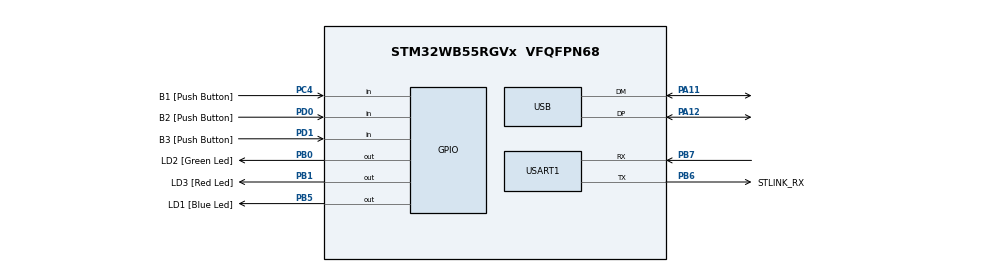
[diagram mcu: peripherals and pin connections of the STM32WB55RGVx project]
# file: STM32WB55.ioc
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Dma.Request0=USART1_TX
Dma.USART1_TX.0.Direction=DMA_MEMORY_TO_PERIPH
Dma.USART1_TX.0.EventEnable=DISABLE
Dma.USART1_TX.0.Instance=DMA1_Channel1
Dma.USART1_TX.0.MemDataAlignment=DMA_MDATAALIGN_BYTE
Dma.USART1_TX.0.MemInc=DMA_MINC_ENABLE
Dma.USART1_TX.0.Mode=DMA_NORMAL
Dma.USART1_TX.0.PeriphDataAlignment=DMA_PDATAALIGN_BYTE
Dma.USART1_TX.0.PeriphInc=DMA_PINC_DISABLE
Dma.USART1_TX.0.Polarity=HAL_DMAMUX_REQ_GEN_RISING
Dma.USART1_TX.0.Priority=DMA_PRIORITY_LOW
Dma.USART1_TX.0.RequestNumber=1
Dma.USART1_TX.0.SignalID=NONE
Dma.USART1_TX.0.SyncEnable=DISABLE
Dma.USART1_TX.0.SyncPolarity=HAL_DMAMUX_SYNC_NO_EVENT
Dma.USART1_TX.0.SyncRequestNumber=1
Dma.USART1_TX.0.SyncSignalID=NONE
Mcu.Family=STM32WB
Mcu.Name=STM32WB55RGVx
Mcu.Package=VFQFPN68
NVIC.DMA1_Channel1_IRQn=true\:0\:0\:false\:false\:true\:false\:true
NVIC.PriorityGroup=NVIC_PRIORITYGROUP_4
NVIC.TIM1_TRG_COM_TIM17_IRQn=true\:0\:0\:false\:false\:true\:false\:true
NVIC.TIM1_UP_TIM16_IRQn=true\:0\:0\:false\:false\:true\:true\:true
NVIC.TIM2_IRQn=true\:0\:0\:false\:false\:true\:true\:true
NVIC.TimeBase=TIM1_TRG_COM_TIM17_IRQn
NVIC.TimeBaseIP=TIM17
NVIC.USART1_IRQn=true\:0\:0\:false\:false\:true\:true\:true
OSC_IN.Mode=HSE-External-Oscillator
OSC_IN.Signal=RCC_OSC_IN
OSC_OUT.Mode=HSE-External-Oscillator
OSC_OUT.Signal=RCC_OSC_OUT
PA11.Mode=Device
PA11.Signal=USB_DM
PA12.Mode=Device
PA12.Signal=USB_DP
PA13.GPIO_Label=JTMS
PA13.Mode=Trace_Asynchronous_SW
PA13.Signal=SYS_JTMS-SWDIO
PA14.GPIO_Label=JTCK
PA14.Mode=Trace_Asynchronous_SW
PA14.Signal=SYS_JTCK-SWCLK
PB0.GPIO_Label=LD2 [Green Led]
PB0.GPIO_Speed=GPIO_SPEED_FREQ_VERY_HIGH
PB0.PinState=GPIO_PIN_RESET
PB0.Signal=GPIO_Output
PB1.GPIO_Label=LD3 [Red Led]
PB1.Signal=GPIO_Output
PB3.GPIO_Label=JTDO
PB3.Mode=Trace_Asynchronous_SW
PB3.Signal=SYS_JTDO-SWO
PB5.GPIO_Label=LD1 [Blue Led]
PB5.Signal=GPIO_Output
PB6.GPIO_Label=STLINK_RX
PB6.GPIO_PuPd=GPIO_PULLUP
PB6.Mode=Asynchronous
PB6.Signal=USART1_TX
PB7.Mode=Asynchronous
PB7.Signal=USART1_RX
PC13.Mode=SYS_WakeUp1
PC13.Signal=SYS_WKUP2
PC14-OSC32_IN.Mode=LSE-External-Oscillator
PC14-OSC32_IN.Signal=RCC_OSC32_IN
PC15-OSC32_OUT.Mode=LSE-External-Oscillator
PC15-OSC32_OUT.Signal=RCC_OSC32_OUT
PC4.GPIO_Label=B1 [Push Button]
PC4.Signal=GPIO_Input
PD0.GPIO_Label=B2 [Push Button]
PD0.Signal=GPIO_Input
PD1.GPIO_Label=B3 [Push Button]
PD1.Signal=GPIO_Input
ProjectManager.HeapSize=0x200
ProjectManager.StackSize=0x400
ProjectManager.TargetToolchain=STM32CubeIDE
RCC.ADCFreq_Value=96000000
RCC.AHB2CLKDivider=RCC_SYSCLK_DIV2
RCC.AHBFreq_Value=64000000
RCC.APB1Freq_Value=64000000
RCC.APB1TimFreq_Value=64000000
RCC.APB2Freq_Value=64000000
RCC.APB2TimFreq_Value=64000000
RCC.APB3Freq_Value=16000000
RCC.CortexFreq_Value=64000000
RCC.HCLKFreq_Value=64000000
RCC.HSEPRES=2
RCC.HSE_VALUE=32000000
RCC.HSI48_VALUE=48000000
RCC.HSI_VALUE=16000000
RCC.PLLM=RCC_PLLM_DIV2
RCC.PLLN=32
RCC.PLLR=RCC_PLLR_DIV4
RCC.PLLSAI1N=24
RCC.PLLSAI1Q=RCC_PLLQ_DIV4
RCC.PLLSourceVirtual=RCC_PLLSOURCE_HSE
RCC.SMPSCLockSelectionVirtual=RCC_SMPSCLKSOURCE_HSI
RCC.SMPSCLockSelectionVirtualVirtual=RCC_SMPSCLKSOURCE_HSI
RCC.SMPSDivider=1
RCC.SYSCLKFreq_VALUE=64000000
RCC.SYSCLKSource=RCC_SYSCLKSOURCE_PLLCLK
RCC.USBFreq_Value=48000000
RCC.VCOOutputFreq_Value=256000000
TIM2.AutoReloadPreload=TIM_AUTORELOAD_PRELOAD_ENABLE
TIM2.Channel-Output\ Compare1\ No\ Output=TIM_CHANNEL_1
TIM2.Channel-Output\ Compare2\ No\ Output=TIM_CHANNEL_2
TIM2.OC1Preload=DISABLE
TIM2.OC2Preload=DISABLE
TIM2.OCMode_1=TIM_OCMODE_TIMING
TIM2.OCMode_2=TIM_OCMODE_TIMING
TIM2.Period=0x0000FFFF
TIM2.Prescaler=64
TIM2.Pulse-Output\ Compare1\ No\ Output=2000
TIM2.Pulse-Output\ Compare2\ No\ Output=10000
USART1.VirtualMode-Asynchronous=VM_ASYNC
VP_CRC_VS_CRC.Mode=CRC_Activate
VP_RTC_VS_RTC_Activate.Mode=RTC_Enabled
VP_SYS_VS_tim17.Mode=TIM17
VP_TIM16_VS_ClockSourceINT.Mode=Enable_Timer
VP_TIM2_VS_ClockSourceINT.Mode=Internal
VP_TIM2_VS_no_output1.Mode=Output Compare1 No Output
VP_TIM2_VS_no_output2.Mode=Output Compare2 No Output
board=P-NUCLEO-WB55-Nucleo

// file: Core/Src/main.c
/* USER CODE BEGIN Header */
/**
  ******************************************************************************
  * @file           : main.c
  * @brief          : Main program body
  ******************************************************************************
  * @attention
  *
  * <h2><center>&copy; Copyright (c) 2022 STMicroelectronics.
  * All rights reserved.</center></h2>
  *
  * This software component is licensed by ST under BSD 3-Clause license,
  * the "License"; You may not use this file except in compliance with the
  * License. You may obtain a copy of the License at:
  *                        opensource.org/licenses/BSD-3-Clause
  *
  ******************************************************************************
  */
/* USER CODE END Header */

#include "main.h"

CRC_HandleTypeDef hcrc;

RTC_HandleTypeDef hrtc;

TIM_HandleTypeDef htim2;
TIM_HandleTypeDef htim16;

DMA_HandleTypeDef hdma_usart1_tx;

PCD_HandleTypeDef hpcd_USB_FS;

void SystemClock_Config(void);
static void MX_GPIO_Init(void);
static void MX_DMA_Init(void);
static void MX_USB_PCD_Init(void);
static void MX_CRC_Init(void);
static void MX_RTC_Init(void);
static void MX_TIM2_Init(void);
static void MX_USART1_UART_Init(void);
static void MX_TIM16_Init(void);

int main(void)
{

  /* MCU Configuration--------------------------------------------------------*/

  /* Reset of all peripherals, Initializes the Flash interface and the Systick. */
  HAL_Init();

  /* Configure the system clock */
  SystemClock_Config();

  /* Initialize all configured peripherals */
  MX_GPIO_Init();
  MX_DMA_Init();
  MX_USB_PCD_Init();
  MX_CRC_Init();
  MX_RTC_Init();
  MX_TIM2_Init();
  MX_USART1_UART_Init();
  MX_TIM16_Init();
  /* USER CODE BEGIN 2 */
  app_main_init();
  /* USER CODE END 2 */

  /* Infinite loop */
  /* USER CODE BEGIN WHILE */
  while (1)
  {
    app_main_idle();
    /* USER CODE END WHILE */

  }
}

void SystemClock_Config(void)
{
  RCC_OscInitTypeDef RCC_OscInitStruct = {0};
  RCC_ClkInitTypeDef RCC_ClkInitStruct = {0};
  RCC_PeriphCLKInitTypeDef PeriphClkInitStruct = {0};

  /** Configure the main internal regulator output voltage
  */
  __HAL_PWR_VOLTAGESCALING_CONFIG(PWR_REGULATOR_VOLTAGE_SCALE1);
  /** Initializes the CPU, AHB and APB busses clocks
  */
  RCC_OscInitStruct.OscillatorType = RCC_OSCILLATORTYPE_HSI|RCC_OSCILLATORTYPE_LSI1
                              |RCC_OSCILLATORTYPE_HSE;
  RCC_OscInitStruct.HSEState = RCC_HSE_ON;
  RCC_OscInitStruct.HSIState = RCC_HSI_ON;
  RCC_OscInitStruct.HSICalibrationValue = RCC_HSICALIBRATION_DEFAULT;
  RCC_OscInitStruct.LSIState = RCC_LSI_ON;
  RCC_OscInitStruct.PLL.PLLState = RCC_PLL_ON;
  RCC_OscInitStruct.PLL.PLLSource = RCC_PLLSOURCE_HSE;
  RCC_OscInitStruct.PLL.PLLM = RCC_PLLM_DIV2;
  RCC_OscInitStruct.PLL.PLLN = 32;
  RCC_OscInitStruct.PLL.PLLP = RCC_PLLP_DIV2;
  RCC_OscInitStruct.PLL.PLLR = RCC_PLLR_DIV4;
  RCC_OscInitStruct.PLL.PLLQ = RCC_PLLQ_DIV2;
  if (HAL_RCC_OscConfig(&RCC_OscInitStruct) != HAL_OK)
  {
    Error_Handler();
  }
  /** Configure the SYSCLKSource, HCLK, PCLK1 and PCLK2 clocks dividers
  */
  RCC_ClkInitStruct.ClockType = RCC_CLOCKTYPE_HCLK4|RCC_CLOCKTYPE_HCLK2
                              |RCC_CLOCKTYPE_HCLK|RCC_CLOCKTYPE_SYSCLK
                              |RCC_CLOCKTYPE_PCLK1|RCC_CLOCKTYPE_PCLK2;
  RCC_ClkInitStruct.SYSCLKSource = RCC_SYSCLKSOURCE_PLLCLK;
  RCC_ClkInitStruct.AHBCLKDivider = RCC_SYSCLK_DIV1;
  RCC_ClkInitStruct.APB1CLKDivider = RCC_HCLK_DIV1;
  RCC_ClkInitStruct.APB2CLKDivider = RCC_HCLK_DIV1;
  RCC_ClkInitStruct.AHBCLK2Divider = RCC_SYSCLK_DIV2;
  RCC_ClkInitStruct.AHBCLK4Divider = RCC_SYSCLK_DIV1;

  if (HAL_RCC_ClockConfig(&RCC_ClkInitStruct, FLASH_LATENCY_3) != HAL_OK)
  {
    Error_Handler();
  }
  /** Enable the HSE Prescaler
  */
  __HAL_RCC_HSE_DIV2_ENABLE();
  /** Initializes the peripherals clocks
  */
  PeriphClkInitStruct.PeriphClockSelection = RCC_PERIPHCLK_SMPS|RCC_PERIPHCLK_RTC
                              |RCC_PERIPHCLK_USART1|RCC_PERIPHCLK_USB;
  PeriphClkInitStruct.PLLSAI1.PLLN = 24;
  PeriphClkInitStruct.PLLSAI1.PLLP = RCC_PLLP_DIV2;
  PeriphClkInitStruct.PLLSAI1.PLLQ = RCC_PLLQ_DIV4;
  PeriphClkInitStruct.PLLSAI1.PLLR = RCC_PLLR_DIV2;
  PeriphClkInitStruct.PLLSAI1.PLLSAI1ClockOut = RCC_PLLSAI1_USBCLK;
  PeriphClkInitStruct.Usart1ClockSelection = RCC_USART1CLKSOURCE_PCLK2;
  PeriphClkInitStruct.UsbClockSelection = RCC_USBCLKSOURCE_PLLSAI1;
  PeriphClkInitStruct.RTCClockSelection = RCC_RTCCLKSOURCE_LSI;
  PeriphClkInitStruct.SmpsClockSelection = RCC_SMPSCLKSOURCE_HSI;
  PeriphClkInitStruct.SmpsDivSelection = RCC_SMPSCLKDIV_RANGE0;
  if (HAL_RCCEx_PeriphCLKConfig(&PeriphClkInitStruct) != HAL_OK)
  {
    Error_Handler();
  }
}

static void MX_CRC_Init(void)
{

  hcrc.Instance = CRC;
  hcrc.Init.DefaultPolynomialUse = DEFAULT_POLYNOMIAL_ENABLE;
  hcrc.Init.DefaultInitValueUse = DEFAULT_INIT_VALUE_ENABLE;
  hcrc.Init.InputDataInversionMode = CRC_INPUTDATA_INVERSION_NONE;
  hcrc.Init.OutputDataInversionMode = CRC_OUTPUTDATA_INVERSION_DISABLE;
  hcrc.InputDataFormat = CRC_INPUTDATA_FORMAT_BYTES;
  if (HAL_CRC_Init(&hcrc) != HAL_OK)
  {
    Error_Handler();
  }

}

static void MX_RTC_Init(void)
{

  /** Initialize RTC Only
  */
  hrtc.Instance = RTC;
  hrtc.Init.HourFormat = RTC_HOURFORMAT_24;
  hrtc.Init.AsynchPrediv = 127;
  hrtc.Init.SynchPrediv = 255;
  hrtc.Init.OutPut = RTC_OUTPUT_DISABLE;
  hrtc.Init.OutPutPolarity = RTC_OUTPUT_POLARITY_HIGH;
  hrtc.Init.OutPutType = RTC_OUTPUT_TYPE_OPENDRAIN;
  hrtc.Init.OutPutRemap = RTC_OUTPUT_REMAP_NONE;
  if (HAL_RTC_Init(&hrtc) != HAL_OK)
  {
    Error_Handler();
  }

}

static void MX_TIM2_Init(void)
{

  TIM_ClockConfigTypeDef sClockSourceConfig = {0};
  TIM_MasterConfigTypeDef sMasterConfig = {0};
  TIM_OC_InitTypeDef sConfigOC = {0};

  htim2.Instance = TIM2;
  htim2.Init.Prescaler = 64;
  htim2.Init.CounterMode = TIM_COUNTERMODE_UP;
  htim2.Init.Period = 0x0000FFFF;
  htim2.Init.ClockDivision = TIM_CLOCKDIVISION_DIV1;
  htim2.Init.AutoReloadPreload = TIM_AUTORELOAD_PRELOAD_ENABLE;
  if (HAL_TIM_Base_Init(&htim2) != HAL_OK)
  {
    Error_Handler();
  }
  sClockSourceConfig.ClockSource = TIM_CLOCKSOURCE_INTERNAL;
  if (HAL_TIM_ConfigClockSource(&htim2, &sClockSourceConfig) != HAL_OK)
  {
    Error_Handler();
  }
  if (HAL_TIM_OC_Init(&htim2) != HAL_OK)
  {
    Error_Handler();
  }
  sMasterConfig.MasterOutputTrigger = TIM_TRGO_RESET;
  sMasterConfig.MasterSlaveMode = TIM_MASTERSLAVEMODE_DISABLE;
  if (HAL_TIMEx_MasterConfigSynchronization(&htim2, &sMasterConfig) != HAL_OK)
  {
    Error_Handler();
  }
  sConfigOC.OCMode = TIM_OCMODE_TIMING;
  sConfigOC.Pulse = 2000;
  sConfigOC.OCPolarity = TIM_OCPOLARITY_HIGH;
  sConfigOC.OCFastMode = TIM_OCFAST_DISABLE;
  if (HAL_TIM_OC_ConfigChannel(&htim2, &sConfigOC, TIM_CHANNEL_1) != HAL_OK)
  {
    Error_Handler();
  }
  sConfigOC.Pulse = 10000;
  if (HAL_TIM_OC_ConfigChannel(&htim2, &sConfigOC, TIM_CHANNEL_2) != HAL_OK)
  {
    Error_Handler();
  }
  /* USER CODE BEGIN TIM2_Init 2 */
  TIM2->EGR |= TIM_EGR_UG;

  TIM2->CR1 |= TIM_CR1_CEN;

  // Enable the NVIC for TIM2
  NVIC_SetPriority(TIM2_IRQn, 0); // Set your desired priority
  NVIC_EnableIRQ(TIM2_IRQn);
  /* USER CODE END TIM2_Init 2 */

}

static void MX_TIM16_Init(void)
{

  htim16.Instance = TIM16;
  htim16.Init.Prescaler = 0;
  htim16.Init.CounterMode = TIM_COUNTERMODE_UP;
  htim16.Init.Period = 0;
  htim16.Init.ClockDivision = TIM_CLOCKDIVISION_DIV1;
  htim16.Init.RepetitionCounter = 0;
  htim16.Init.AutoReloadPreload = TIM_AUTORELOAD_PRELOAD_DISABLE;
  if (HAL_TIM_Base_Init(&htim16) != HAL_OK)
  {
    Error_Handler();
  }

}

static void MX_USART1_UART_Init(void)
{

  huart1.Instance = USART1;
  huart1.Init.BaudRate = 115200;
  huart1.Init.WordLength = UART_WORDLENGTH_8B;
  huart1.Init.StopBits = UART_STOPBITS_1;
  huart1.Init.Parity = UART_PARITY_NONE;
  huart1.Init.Mode = UART_MODE_TX_RX;
  huart1.Init.HwFlowCtl = UART_HWCONTROL_NONE;
  huart1.Init.OverSampling = UART_OVERSAMPLING_16;
  huart1.Init.OneBitSampling = UART_ONE_BIT_SAMPLE_DISABLE;
  huart1.Init.ClockPrescaler = UART_PRESCALER_DIV1;
  huart1.AdvancedInit.AdvFeatureInit = UART_ADVFEATURE_NO_INIT;
  if (HAL_UART_Init(&huart1) != HAL_OK)
  {
    Error_Handler();
  }
  if (HAL_UARTEx_SetTxFifoThreshold(&huart1, UART_TXFIFO_THRESHOLD_1_8) != HAL_OK)
  {
    Error_Handler();
  }
  if (HAL_UARTEx_SetRxFifoThreshold(&huart1, UART_RXFIFO_THRESHOLD_1_8) != HAL_OK)
  {
    Error_Handler();
  }
  if (HAL_UARTEx_DisableFifoMode(&huart1) != HAL_OK)
  {
    Error_Handler();
  }

}

static void MX_USB_PCD_Init(void)
{

  hpcd_USB_FS.Instance = USB;
  hpcd_USB_FS.Init.dev_endpoints = 8;
  hpcd_USB_FS.Init.speed = PCD_SPEED_FULL;
  hpcd_USB_FS.Init.phy_itface = PCD_PHY_EMBEDDED;
  hpcd_USB_FS.Init.Sof_enable = DISABLE;
  hpcd_USB_FS.Init.low_power_enable = DISABLE;
  hpcd_USB_FS.Init.lpm_enable = DISABLE;
  hpcd_USB_FS.Init.battery_charging_enable = DISABLE;
  if (HAL_PCD_Init(&hpcd_USB_FS) != HAL_OK)
  {
    Error_Handler();
  }

}

static void MX_DMA_Init(void)
{

  /* DMA controller clock enable */
  __HAL_RCC_DMAMUX1_CLK_ENABLE();
  __HAL_RCC_DMA1_CLK_ENABLE();

  /* DMA interrupt init */
  /* DMA1_Channel1_IRQn interrupt configuration */
  HAL_NVIC_SetPriority(DMA1_Channel1_IRQn, 0, 0);
  HAL_NVIC_EnableIRQ(DMA1_Channel1_IRQn);

}

static void MX_GPIO_Init(void)
{
  GPIO_InitTypeDef GPIO_InitStruct = {0};

  /* GPIO Ports Clock Enable */
  __HAL_RCC_GPIOC_CLK_ENABLE();
  __HAL_RCC_GPIOB_CLK_ENABLE();
  __HAL_RCC_GPIOA_CLK_ENABLE();
  __HAL_RCC_GPIOD_CLK_ENABLE();

  /*Configure GPIO pin Output Level */
  HAL_GPIO_WritePin(GPIOB, LD2_Pin|LD3_Pin|LD1_Pin, GPIO_PIN_RESET);

  /*Configure GPIO pin : B1_Pin */
  GPIO_InitStruct.Pin = B1_Pin;
  GPIO_InitStruct.Mode = GPIO_MODE_INPUT;
  GPIO_InitStruct.Pull = GPIO_NOPULL;
  HAL_GPIO_Init(B1_GPIO_Port, &GPIO_InitStruct);

  /*Configure GPIO pin : LD2_Pin */
  GPIO_InitStruct.Pin = LD2_Pin;
  GPIO_InitStruct.Mode = GPIO_MODE_OUTPUT_PP;
  GPIO_InitStruct.Pull = GPIO_NOPULL;
  GPIO_InitStruct.Speed = GPIO_SPEED_FREQ_VERY_HIGH;
  HAL_GPIO_Init(LD2_GPIO_Port, &GPIO_InitStruct);

  /*Configure GPIO pins : LD3_Pin LD1_Pin */
  GPIO_InitStruct.Pin = LD3_Pin|LD1_Pin;
  GPIO_InitStruct.Mode = GPIO_MODE_OUTPUT_PP;
  GPIO_InitStruct.Pull = GPIO_NOPULL;
  GPIO_InitStruct.Speed = GPIO_SPEED_FREQ_LOW;
  HAL_GPIO_Init(GPIOB, &GPIO_InitStruct);

  /*Configure GPIO pins : B2_Pin B3_Pin */
  GPIO_InitStruct.Pin = B2_Pin|B3_Pin;
  GPIO_InitStruct.Mode = GPIO_MODE_INPUT;
  GPIO_InitStruct.Pull = GPIO_NOPULL;
  HAL_GPIO_Init(GPIOD, &GPIO_InitStruct);

}

 /**
  * @brief  Period elapsed callback in non blocking mode
  * @note   This function is called  when TIM17 interrupt took place, inside
  * HAL_TIM_IRQHandler(). It makes a direct call to HAL_IncTick() to increment
  * a global variable "uwTick" used as application time base.
  * @param  htim : TIM handle
  * @retval None
  */
void HAL_TIM_PeriodElapsedCallback(TIM_HandleTypeDef *htim)
{
  if (htim->Instance == TIM17) {
    HAL_IncTick();
  }
}

void Error_Handler(void)
{
}

/************************ (C) COPYRIGHT STMicroelectronics *****END OF FILE****/
